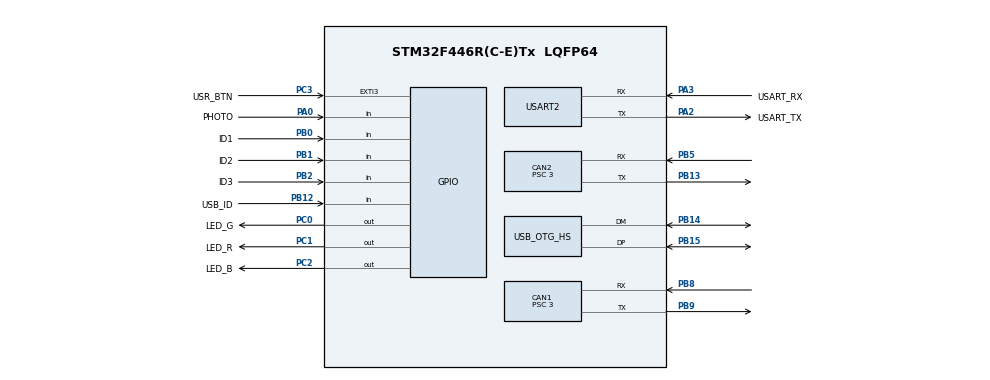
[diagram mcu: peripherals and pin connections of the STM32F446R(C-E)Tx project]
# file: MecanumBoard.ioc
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CAN1.BS1=CAN_BS1_10TQ
CAN1.BS2=CAN_BS2_4TQ
CAN1.CalculateBaudRate=1000000
CAN1.CalculateTimeBit=1000
CAN1.CalculateTimeQuantum=66.66666666666666
CAN1.NART=ENABLE
CAN1.Prescaler=3
CAN2.BS1=CAN_BS1_10TQ
CAN2.BS2=CAN_BS2_4TQ
CAN2.CalculateBaudRate=1000000
CAN2.CalculateTimeBit=1000
CAN2.CalculateTimeQuantum=66.66666666666666
CAN2.NART=ENABLE
CAN2.Prescaler=3
Mcu.Family=STM32F4
Mcu.Name=STM32F446R(C-E)Tx
Mcu.Package=LQFP64
NVIC.CAN1_RX0_IRQn=true\:0\:2\:false\:false\:true\:true\:true\:true
NVIC.CAN1_RX1_IRQn=true\:0\:2\:false\:false\:true\:true\:true\:true
NVIC.CAN2_RX0_IRQn=true\:0\:2\:false\:false\:true\:true\:true\:true
NVIC.CAN2_RX1_IRQn=true\:0\:2\:false\:false\:true\:true\:true\:true
NVIC.EXTI3_IRQn=true\:0\:3\:false\:false\:true\:true\:true\:true
NVIC.OTG_HS_IRQn=true\:0\:1\:false\:false\:true\:false\:true\:true
NVIC.PriorityGroup=NVIC_PRIORITYGROUP_0
NVIC.TIM5_IRQn=true\:0\:0\:false\:false\:true\:true\:true\:true
NVIC.TIM8_TRG_COM_TIM14_IRQn=true\:0\:15\:false\:false\:true\:true\:true\:true
PA0-WKUP.GPIO_Label=PHOTO
PA0-WKUP.GPIO_PuPd=GPIO_PULLUP
PA0-WKUP.Signal=GPIO_Input
PA13.GPIO_Label=TMS
PA13.Mode=Serial_Wire
PA13.Signal=SYS_JTMS-SWDIO
PA14.GPIO_Label=TCK
PA14.Mode=Serial_Wire
PA14.Signal=SYS_JTCK-SWCLK
PA2.GPIO_Label=USART_TX
PA2.Mode=Asynchronous
PA2.Signal=USART2_TX
PA3.GPIO_Label=USART_RX
PA3.Mode=Asynchronous
PA3.Signal=USART2_RX
PB0.GPIO_Label=ID1
PB0.GPIO_PuPd=GPIO_PULLUP
PB0.Signal=GPIO_Input
PB1.GPIO_Label=ID2
PB1.GPIO_PuPd=GPIO_PULLUP
PB1.Signal=GPIO_Input
PB12.GPIO_Label=USB_ID
PB12.GPIO_PuPd=GPIO_NOPULL
PB12.Signal=GPIO_Input
PB13.Mode=CAN_Activate
PB13.Signal=CAN2_TX
PB14.Mode=Device_Only_FS
PB14.Signal=USB_OTG_HS_DM
PB15.Mode=Device_Only_FS
PB15.Signal=USB_OTG_HS_DP
PB2.GPIO_Label=ID3
PB2.GPIO_PuPd=GPIO_PULLUP
PB2.Signal=GPIO_Input
PB3.GPIO_Label=SWO
PB3.Signal=SYS_JTDO-SWO
PB5.Mode=CAN_Activate
PB5.Signal=CAN2_RX
PB8.Mode=CAN_Activate
PB8.Signal=CAN1_RX
PB9.Mode=CAN_Activate
PB9.Signal=CAN1_TX
PC0.GPIO_Label=LED_G
PC0.Signal=GPIO_Output
PC1.GPIO_Label=LED_R
PC1.Signal=GPIO_Output
PC2.GPIO_Label=LED_B
PC2.Signal=GPIO_Output
PC3.GPIO_Label=USR_BTN
PC3.GPIO_ModeDefaultEXTI=GPIO_MODE_IT_RISING_FALLING
PC3.GPIO_PuPd=GPIO_PULLUP
PC3.Signal=GPXTI3
PH0-OSC_IN.Mode=HSE-External-Oscillator
PH0-OSC_IN.Signal=RCC_OSC_IN
PH1-OSC_OUT.Mode=HSE-External-Oscillator
PH1-OSC_OUT.Signal=RCC_OSC_OUT
ProjectManager.HeapSize=0x200
ProjectManager.StackSize=0x400
ProjectManager.TargetToolchain=STM32CubeIDE
RCC.48MHZClocksFreq_Value=84000000
RCC.AHBFreq_Value=180000000
RCC.APB1CLKDivider=RCC_HCLK_DIV4
RCC.APB1Freq_Value=45000000
RCC.APB1TimFreq_Value=90000000
RCC.APB2CLKDivider=RCC_HCLK_DIV4
RCC.APB2Freq_Value=45000000
RCC.APB2TimFreq_Value=90000000
RCC.CortexFreq_Value=180000000
RCC.FLatency-AdvancedSettings=FLASH_LATENCY_5
RCC.HCLKFreq_Value=180000000
RCC.HSE_VALUE=12000000
RCC.HSI_VALUE=16000000
RCC.PLLM=6
RCC.PLLN=180
RCC.PLLSAIM=6
RCC.PLLSAIN=96
RCC.PLLSAIP=RCC_PLLSAIP_DIV4
RCC.SYSCLKFreq_VALUE=180000000
RCC.SYSCLKSource=RCC_SYSCLKSOURCE_PLLCLK
RCC.USBCLockSelection=RCC_CLK48CLKSOURCE_PLLSAIP
RCC.USBFreq_Value=48000000
RCC.VCOOutputFreq_Value=360000000
TIM14.Period=1000 - 1
TIM14.Prescaler=90 - 1
TIM5.Prescaler=90 - 1
USART2.VirtualMode=VM_ASYNC
USB_DEVICE.CLASS_NAME_HS=CDC
USB_DEVICE.VirtualMode-CDC_HS=Cdc
USB_DEVICE.VirtualModeHS=Cdc_HS
USB_OTG_HS.VirtualMode-Device_Only_FS=Device_Only_FS
VP_TIM14_VS_ClockSourceINT.Mode=Enable_Timer
VP_TIM5_VS_ClockSourceINT.Mode=Internal
VP_USB_DEVICE_VS_USB_DEVICE_CDC_HS.Mode=CDC_HS
board=NUCLEO-F446RE

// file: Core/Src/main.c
/* USER CODE BEGIN Header */
/**
  ******************************************************************************
  * @file           : main.c
  * @brief          : Main program body
  ******************************************************************************
  * @attention
  *
  * Copyright (c) 2025 STMicroelectronics.
  * All rights reserved.
  *
  * This software is licensed under terms that can be found in the LICENSE file
  * in the root directory of this software component.
  * If no LICENSE file comes with this software, it is provided AS-IS.
  *
  ******************************************************************************
  */
/* USER CODE END Header */
#include "main.h"
#include "usb_device.h"

CAN_HandleTypeDef hcan1;
CAN_HandleTypeDef hcan2;

TIM_HandleTypeDef htim5;
TIM_HandleTypeDef htim14;

UART_HandleTypeDef huart2;

void SystemClock_Config(void);
static void MX_GPIO_Init(void);
static void MX_USART2_UART_Init(void);
static void MX_TIM5_Init(void);
static void MX_TIM14_Init(void);
static void MX_CAN1_Init(void);
static void MX_CAN2_Init(void);

int main(void)
{

  /* MCU Configuration--------------------------------------------------------*/

  /* Reset of all peripherals, Initializes the Flash interface and the Systick. */
  HAL_Init();

  /* Configure the system clock */
  SystemClock_Config();

  /* Initialize all configured peripherals */
  MX_GPIO_Init();
  MX_USART2_UART_Init();
  MX_TIM5_Init();
  MX_TIM14_Init();
  MX_USB_DEVICE_Init();
  MX_CAN1_Init();
  MX_CAN2_Init();

  /* Infinite loop */
  while (1)
  {

  }
}

void SystemClock_Config(void)
{
  RCC_OscInitTypeDef RCC_OscInitStruct = {0};
  RCC_ClkInitTypeDef RCC_ClkInitStruct = {0};

  /** Configure the main internal regulator output voltage
  */
  __HAL_RCC_PWR_CLK_ENABLE();
  __HAL_PWR_VOLTAGESCALING_CONFIG(PWR_REGULATOR_VOLTAGE_SCALE1);

  /** Initializes the RCC Oscillators according to the specified parameters
  * in the RCC_OscInitTypeDef structure.
  */
  RCC_OscInitStruct.OscillatorType = RCC_OSCILLATORTYPE_HSE;
  RCC_OscInitStruct.HSEState = RCC_HSE_ON;
  RCC_OscInitStruct.PLL.PLLState = RCC_PLL_ON;
  RCC_OscInitStruct.PLL.PLLSource = RCC_PLLSOURCE_HSE;
  RCC_OscInitStruct.PLL.PLLM = 6;
  RCC_OscInitStruct.PLL.PLLN = 180;
  RCC_OscInitStruct.PLL.PLLP = RCC_PLLP_DIV2;
  RCC_OscInitStruct.PLL.PLLQ = 2;
  RCC_OscInitStruct.PLL.PLLR = 2;
  if (HAL_RCC_OscConfig(&RCC_OscInitStruct) != HAL_OK)
  {
    Error_Handler();
  }

  /** Activate the Over-Drive mode
  */
  if (HAL_PWREx_EnableOverDrive() != HAL_OK)
  {
    Error_Handler();
  }

  /** Initializes the CPU, AHB and APB buses clocks
  */
  RCC_ClkInitStruct.ClockType = RCC_CLOCKTYPE_HCLK|RCC_CLOCKTYPE_SYSCLK
                              |RCC_CLOCKTYPE_PCLK1|RCC_CLOCKTYPE_PCLK2;
  RCC_ClkInitStruct.SYSCLKSource = RCC_SYSCLKSOURCE_PLLCLK;
  RCC_ClkInitStruct.AHBCLKDivider = RCC_SYSCLK_DIV1;
  RCC_ClkInitStruct.APB1CLKDivider = RCC_HCLK_DIV4;
  RCC_ClkInitStruct.APB2CLKDivider = RCC_HCLK_DIV2;

  if (HAL_RCC_ClockConfig(&RCC_ClkInitStruct, FLASH_LATENCY_5) != HAL_OK)
  {
    Error_Handler();
  }
}

static void MX_CAN1_Init(void)
{

  hcan1.Instance = CAN1;
  hcan1.Init.Prescaler = 3;
  hcan1.Init.Mode = CAN_MODE_NORMAL;
  hcan1.Init.SyncJumpWidth = CAN_SJW_1TQ;
  hcan1.Init.TimeSeg1 = CAN_BS1_10TQ;
  hcan1.Init.TimeSeg2 = CAN_BS2_4TQ;
  hcan1.Init.TimeTriggeredMode = DISABLE;
  hcan1.Init.AutoBusOff = DISABLE;
  hcan1.Init.AutoWakeUp = DISABLE;
  hcan1.Init.AutoRetransmission = ENABLE;
  hcan1.Init.ReceiveFifoLocked = DISABLE;
  hcan1.Init.TransmitFifoPriority = DISABLE;
  if (HAL_CAN_Init(&hcan1) != HAL_OK)
  {
    Error_Handler();
  }

}

static void MX_CAN2_Init(void)
{

  hcan2.Instance = CAN2;
  hcan2.Init.Prescaler = 3;
  hcan2.Init.Mode = CAN_MODE_NORMAL;
  hcan2.Init.SyncJumpWidth = CAN_SJW_1TQ;
  hcan2.Init.TimeSeg1 = CAN_BS1_10TQ;
  hcan2.Init.TimeSeg2 = CAN_BS2_4TQ;
  hcan2.Init.TimeTriggeredMode = DISABLE;
  hcan2.Init.AutoBusOff = DISABLE;
  hcan2.Init.AutoWakeUp = DISABLE;
  hcan2.Init.AutoRetransmission = ENABLE;
  hcan2.Init.ReceiveFifoLocked = DISABLE;
  hcan2.Init.TransmitFifoPriority = DISABLE;
  if (HAL_CAN_Init(&hcan2) != HAL_OK)
  {
    Error_Handler();
  }

}

static void MX_TIM5_Init(void)
{

  TIM_ClockConfigTypeDef sClockSourceConfig = {0};
  TIM_MasterConfigTypeDef sMasterConfig = {0};

  htim5.Instance = TIM5;
  htim5.Init.Prescaler = 90 - 1;
  htim5.Init.CounterMode = TIM_COUNTERMODE_UP;
  htim5.Init.Period = 4294967295;
  htim5.Init.ClockDivision = TIM_CLOCKDIVISION_DIV1;
  htim5.Init.AutoReloadPreload = TIM_AUTORELOAD_PRELOAD_DISABLE;
  if (HAL_TIM_Base_Init(&htim5) != HAL_OK)
  {
    Error_Handler();
  }
  sClockSourceConfig.ClockSource = TIM_CLOCKSOURCE_INTERNAL;
  if (HAL_TIM_ConfigClockSource(&htim5, &sClockSourceConfig) != HAL_OK)
  {
    Error_Handler();
  }
  sMasterConfig.MasterOutputTrigger = TIM_TRGO_RESET;
  sMasterConfig.MasterSlaveMode = TIM_MASTERSLAVEMODE_DISABLE;
  if (HAL_TIMEx_MasterConfigSynchronization(&htim5, &sMasterConfig) != HAL_OK)
  {
    Error_Handler();
  }

}

static void MX_TIM14_Init(void)
{

  htim14.Instance = TIM14;
  htim14.Init.Prescaler = 90 - 1;
  htim14.Init.CounterMode = TIM_COUNTERMODE_UP;
  htim14.Init.Period = 1000 - 1;
  htim14.Init.ClockDivision = TIM_CLOCKDIVISION_DIV1;
  htim14.Init.AutoReloadPreload = TIM_AUTORELOAD_PRELOAD_DISABLE;
  if (HAL_TIM_Base_Init(&htim14) != HAL_OK)
  {
    Error_Handler();
  }

}

static void MX_USART2_UART_Init(void)
{

  huart2.Instance = USART2;
  huart2.Init.BaudRate = 115200;
  huart2.Init.WordLength = UART_WORDLENGTH_8B;
  huart2.Init.StopBits = UART_STOPBITS_1;
  huart2.Init.Parity = UART_PARITY_NONE;
  huart2.Init.Mode = UART_MODE_TX_RX;
  huart2.Init.HwFlowCtl = UART_HWCONTROL_NONE;
  huart2.Init.OverSampling = UART_OVERSAMPLING_16;
  if (HAL_UART_Init(&huart2) != HAL_OK)
  {
    Error_Handler();
  }

}

static void MX_GPIO_Init(void)
{
  GPIO_InitTypeDef GPIO_InitStruct = {0};

  /* GPIO Ports Clock Enable */
  __HAL_RCC_GPIOH_CLK_ENABLE();
  __HAL_RCC_GPIOC_CLK_ENABLE();
  __HAL_RCC_GPIOA_CLK_ENABLE();
  __HAL_RCC_GPIOB_CLK_ENABLE();

  /*Configure GPIO pin Output Level */
  HAL_GPIO_WritePin(GPIOC, LED_G_Pin|LED_R_Pin|LED_B_Pin, GPIO_PIN_RESET);

  /*Configure GPIO pins : LED_G_Pin LED_R_Pin LED_B_Pin */
  GPIO_InitStruct.Pin = LED_G_Pin|LED_R_Pin|LED_B_Pin;
  GPIO_InitStruct.Mode = GPIO_MODE_OUTPUT_PP;
  GPIO_InitStruct.Pull = GPIO_NOPULL;
  GPIO_InitStruct.Speed = GPIO_SPEED_FREQ_LOW;
  HAL_GPIO_Init(GPIOC, &GPIO_InitStruct);

  /*Configure GPIO pin : USR_BTN_Pin */
  GPIO_InitStruct.Pin = USR_BTN_Pin;
  GPIO_InitStruct.Mode = GPIO_MODE_IT_RISING_FALLING;
  GPIO_InitStruct.Pull = GPIO_PULLUP;
  HAL_GPIO_Init(USR_BTN_GPIO_Port, &GPIO_InitStruct);

  /*Configure GPIO pin : PHOTO_Pin */
  GPIO_InitStruct.Pin = PHOTO_Pin;
  GPIO_InitStruct.Mode = GPIO_MODE_INPUT;
  GPIO_InitStruct.Pull = GPIO_PULLUP;
  HAL_GPIO_Init(PHOTO_GPIO_Port, &GPIO_InitStruct);

  /*Configure GPIO pins : ID1_Pin ID2_Pin ID3_Pin */
  GPIO_InitStruct.Pin = ID1_Pin|ID2_Pin|ID3_Pin;
  GPIO_InitStruct.Mode = GPIO_MODE_INPUT;
  GPIO_InitStruct.Pull = GPIO_PULLUP;
  HAL_GPIO_Init(GPIOB, &GPIO_InitStruct);

  /*Configure GPIO pin : USB_ID_Pin */
  GPIO_InitStruct.Pin = USB_ID_Pin;
  GPIO_InitStruct.Mode = GPIO_MODE_INPUT;
  GPIO_InitStruct.Pull = GPIO_NOPULL;
  HAL_GPIO_Init(USB_ID_GPIO_Port, &GPIO_InitStruct);

  /* EXTI interrupt init*/
  HAL_NVIC_SetPriority(EXTI3_IRQn, 0, 3);
  HAL_NVIC_EnableIRQ(EXTI3_IRQn);

}

void Error_Handler(void)
{
  __disable_irq();
  while (1)
  {
  }
}
